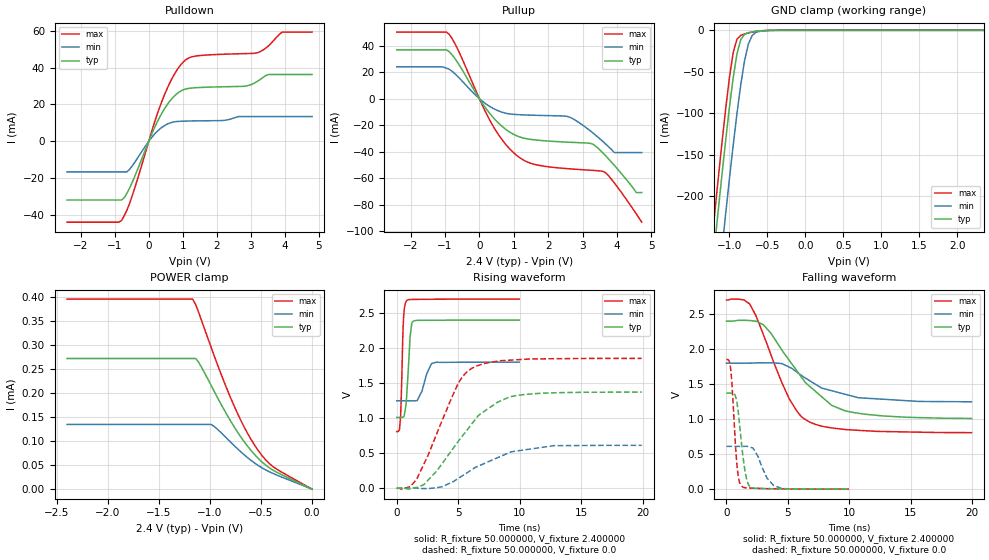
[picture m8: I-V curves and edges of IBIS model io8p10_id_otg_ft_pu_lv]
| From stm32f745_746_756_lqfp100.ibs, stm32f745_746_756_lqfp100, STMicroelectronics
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|   Model io8p10_id_otg_ft_pu_lv
[Model]  io8p10_id_otg_ft_pu_lv
Model_type I/O
Polarity   Non-Inverting
Enable   Active-Low
Vinl =   0.720000V
Vinh =   1.680000V
Vmeas =  1.200000V
Cref =   40.000000pF
Rref =   100.000000M
Vref =   0.0V
C_comp   2.229800pF   2.169700pF   2.325100pF
[Temperature Range]   25.000000   0.125000k   -40.000000
[Pullup Reference]   2.400000V   1.800000V   2.700000V
[Pulldown Reference]   0.0V   0.0V   0.0V
[POWER Clamp Reference]   2.400000V   1.800000V   2.700000V
[GND Clamp Reference]   0.0V   0.0V   0.0V
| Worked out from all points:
|   slope of the pulldown table from 0 to 0.36 V, typ, clamps not added: 25 ohm
|   slope of the pullup table from 0 to 0.36 V, typ, clamps not added: 27.7 ohm
|   GND clamp passes 1 mA (typ) near -0.62 V on its own axis
|   rising waveform, R_fixture 50.000000, V_fixture 2.400000: 20-80 % time 276ps typ, 615ps min, 181ps max; typ from 1.01 V to 2.4 V
|   rising waveform, R_fixture 50.000000, V_fixture 0.0: 20-80 % time 3.75ns typ, 4.05ns min, 2.68ns max; typ from 0.004 V to 1.37 V
|   falling waveform, R_fixture 50.000000, V_fixture 2.400000: 20-80 % time 3.95ns typ, 4ns min, 2.73ns max; typ from 2.4 V to 1.01 V
|   falling waveform, R_fixture 50.000000, V_fixture 0.0: 20-80 % time 532ps typ, 989ps min, 386ps max; typ from 1.37 V to 0.004 V
[Pulldown]
|Voltage   I(typ)   I(min)   I(max)
-2.4V     -31.73mA   -16.51mA   -43.74mA
-800mV    -31.73mA   -16.51mA   -42.87mA
-480mV    -21.97mA   -13.17mA   -29.21mA
80mV      3.63mA     1.966mA    5.014mA
480mV     18.15mA    8.737mA    26.02mA
800mV     25.37mA    10.72mA    37.77mA
1.12V     28.53mA    11.02mA    44.6mA
2.8V      29.84mA    13.46mA    47.53mA
3.2V      32.6mA     13.46mA    48.03mA
3.52V     36.23mA    13.46mA    51.75mA
3.92V     36.23mA    13.46mA    59.19mA
4.8V      36.23mA    13.46mA    59.19mA
[Pullup]
|Voltage   I(typ)   I(min)   I(max)
-2.4V     36.81mA    24.03mA    50.22mA
-960mV    36.81mA    22.97mA    50.22mA
-640mV    27.62mA    17.02mA    37.95mA
320mV     -11.75mA   -6.206mA   -17.08mA
960mV     -26.46mA   -11.81mA   -40.01mA
1.52V     -30.88mA   -12.51mA   -49.04mA
2.56V     -32.87mA   -13.48mA   -52.89mA
3.28V     -34.17mA   -25.52mA   -54.16mA
3.6V      -41.29mA   -32.61mA   -54.95mA
3.92V     -50.31mA   -40.7mA    -63.6mA
4.56V     -70.9mA    -40.7mA    -87.04mA
4.72V     -70.9mA    -40.7mA    -93.3mA
[GND_clamp]
|Voltage   I(typ)   I(min)   I(max)
-2.4V     -1.424A    -1.508A    -1.393A
-1.25V    -311.2mA   -401.9mA   -273.3mA
-1.2V     -265.4mA   -356.1mA   -227.2mA
-1.15V    -220.4mA   -310.8mA   -181.9mA
-1.1V     -176.3mA   -266.2mA   -137.9mA
-1.05V    -133.8mA   -222.5mA   -95.88mA
-950mV    -57.31mA   -138.9mA   -26.99mA
-900mV    -28.28mA   -100.4mA   -10.61mA
-850mV    -11.02mA   -65.55mA   -5.978mA
-750mV    -2.847mA   -16.51mA   -3.192mA
-600mV    -755.4uA   -1.17mA    -743.6uA
2.35V     0A         0A         0A
[POWER_clamp]
|Voltage   I(typ)   I(min)   I(max)
-2.4V     272.5uA    135uA      396.5uA
-1.17V    272.5uA    135uA      396.5uA
-1.14V    272.5uA    135uA      384.7uA
-1.11V    264.2uA    135uA      368uA
-990mV    216.8uA    135uA      296.5uA
-870mV    168.8uA    113.3uA    228.2uA
-750mV    125.6uA    88.19uA    167.1uA
-660mV    97.6uA     70.82uA    127.5uA
-570mV    73.91uA    55.62uA    94.12uA
-480mV    54.73uA    43.14uA    67.37uA
-390mV    40.65uA    33.48uA    48.23uA
0V        0A         0A         0A
[Ramp]
| variable   typ   min   max
dV/dt_r  0.82171/3.74541n   0.36677/4.05475n   1.11308/2.68853n
dV/dt_f  0.83058/3.95989n   0.33120/4.06752n   1.13384/2.73321n
R_load = 50.000000
[Rising Waveform]
R_fixture= 50.000000
V_fixture= 2.400000
V_fixture_min= 1.800000
V_fixture_max= 2.700000
|time   V(typ)   V(min)   V(max)
0s        1.011V     1.249V     809.2mV
220.2ps   1.011V     1.249V     836.1mV
300.3ps   1.011V     1.249V     995.6mV
560.6ps   1.02V      1.249V     2.447V
800.8ps   1.296V     1.249V     2.674V
1.081ns   2.143V     1.249V     2.693V
1.341ns   2.383V     1.247V     2.694V
2.042ns   2.396V     1.382V     2.695V
2.843ns   2.397V     1.78V      2.697V
9.97ns    2.4V       1.8V       2.699V
[Rising Waveform]
R_fixture= 50.000000
V_fixture= 0.0
V_fixture_min= 0.0
V_fixture_max= 0.0
|time   V(typ)   V(min)   V(max)
0s        3.745mV    3.286mV    4.353mV
1.121ns   -5.002mV   3.344mV    27.75mV
1.642ns   12.38mV    2.72mV     138mV
3.283ns   253.4mV    9.922mV    791.1mV
4.965ns   661.2mV    137.1mV    1.484V
6.206ns   940.8mV    277.4mV    1.721V
8.168ns   1.225V     434.7mV    1.813V
9.409ns   1.313V     523.7mV    1.83V
12.77ns   1.362V     608.8mV    1.849V
19.94ns   1.373V     613.5mV    1.853V
[Falling Waveform]
R_fixture= 50.000000
V_fixture= 2.400000
V_fixture_min= 1.800000
V_fixture_max= 2.700000
|time   V(typ)   V(min)   V(max)
0s        2.4V       1.8V       2.699V
1.121ns   2.41V      1.8V       2.71V
1.882ns   2.407V     1.801V     2.645V
3.003ns   2.348V     1.805V     2.207V
5.125ns   1.836V     1.742V     1.287V
6.046ns   1.614V     1.632V     1.047V
6.807ns   1.464V     1.546V     957.1mV
8.569ns   1.198V     1.406V     876.4mV
9.89ns    1.111V     1.346V     850.7mV
19.94ns   1.011V     1.249V     809.2mV
[Falling Waveform]
R_fixture= 50.000000
V_fixture= 0.0
V_fixture_min= 0.0
V_fixture_max= 0.0
|time   V(typ)   V(min)   V(max)
0s        1.373V     613.5mV    1.853V
340.3ps   1.373V     613.5mV    1.723V
440.4ps   1.373V     613.5mV    1.525V
700.7ps   1.349V     613.4mV    737.2mV
940.9ps   1.131V     613.2mV    211.5mV
1.241ns   630.2mV    613mV      45.65mV
1.682ns   115.7mV    614.8mV    20.53mV
2.042ns   28.2mV     595.9mV    17.62mV
3.844ns   9.408mV    55.16mV    8.721mV
9.97ns    3.745mV    3.286mV    4.353mV
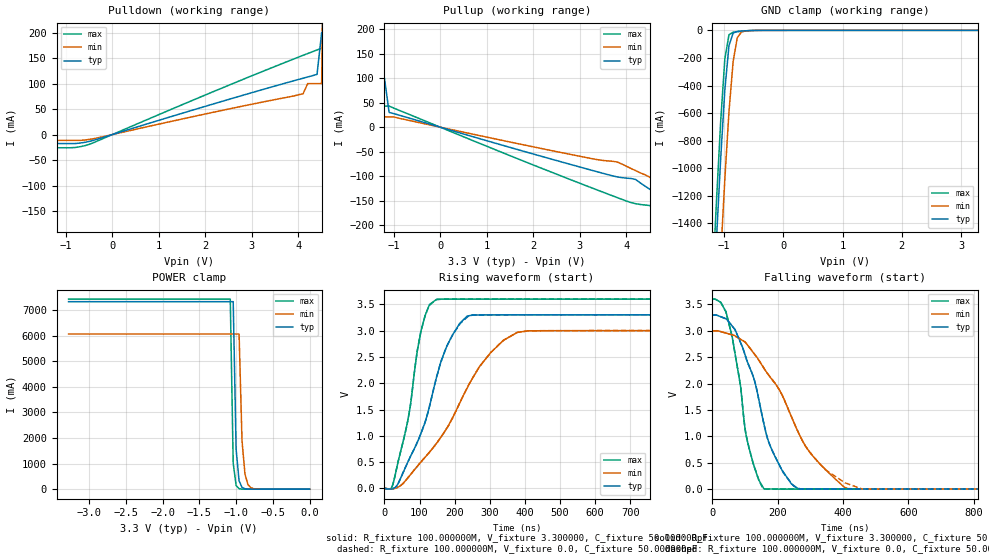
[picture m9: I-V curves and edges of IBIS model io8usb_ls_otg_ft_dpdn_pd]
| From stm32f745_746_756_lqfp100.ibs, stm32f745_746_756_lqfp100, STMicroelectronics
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|   Model io8usb_ls_otg_ft_dpdn_pd
[Model]  io8usb_ls_otg_ft_dpdn_pd
Model_type I/O
Polarity   Non-Inverting
Enable   Active-Low
Vinl =   0.990000V
Vinh =   2.310000V
Vmeas =  1.650000V
Cref =   50.000000pF
Rref =   100.000000M
Vref =   0.0V
C_comp   8.255900pF   7.991100pF   8.650600pF
[Temperature Range]   25.000000   0.125000k   -40.000000
[Pullup Reference]   3.300000V   3.000000V   3.600000V
[Pulldown Reference]   0.0V   0.0V   0.0V
[POWER Clamp Reference]   3.300000V   3.000000V   3.600000V
[GND Clamp Reference]   0.0V   0.0V   0.0V
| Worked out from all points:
|   slope of the pulldown table from 0 to 0.495 V, typ, clamps not added: 35.6 ohm
|   slope of the pullup table from 0 to 0.495 V, typ, clamps not added: 36.1 ohm
|   GND clamp passes 1 mA (typ) near -0.52 V on its own axis
|   POWER clamp passes 1 mA (typ) near -0.81 V on its own axis
|   rising waveform, R_fixture 100.000000M, V_fixture 3.300000, C_fixture 50.000000pF: 20-80 % time 95.9ns typ, 164ns min, 54.2ns max; typ from 0 V to 3.3 V
|   rising waveform, R_fixture 100.000000M, V_fixture 0.0, C_fixture 50.000000pF: 20-80 % time 95.9ns typ, 164ns min, 54ns max; typ from 0 V to 3.3 V
|   falling waveform, R_fixture 100.000000M, V_fixture 3.300000, C_fixture 50.000000pF: 20-80 % time 93.4ns typ, 165ns min, 53.9ns max; typ from 3.3 V to 0 V
|   falling waveform, R_fixture 100.000000M, V_fixture 0.0, C_fixture 50.000000pF: 20-80 % time 93.5ns typ, 165ns min, 53.9ns max; typ from 3.3 V to 0 V
[Pulldown]
|Voltage   I(typ)   I(min)   I(max)
-3.3V     -182mA     -11.47mA   -25.86mA
-3.2V     -17.62mA   -11.47mA   -25.86mA
-600mV    -15.36mA   -10.76mA   -22.01mA
4.1V      110.5mA    80mA       155.3mA
4.2V      112.9mA    100mA      158.9mA
4.4V      118mA      100mA      165.9mA
4.5V      200mA      100mA      169.3mA
4.6V      200mA      1A         172.7mA
4.7V      200mA      1A         176mA
4.8V      1A         1A         200mA
5.4V      1A         1A         1A
6.6V      1A         1A         1A
[Pullup]
|Voltage   I(typ)   I(min)   I(max)
-3.3V     1A         1A         1A
-1.9V     1A         1A         1A
-1.8V     100mA      1A         1A
-1.7V     100mA      1A         100mA
-1.6V     100mA      1A         100mA
-1.5V     100mA      21mA       100mA
-1.3V     100mA      21mA       100mA
-1.2V     100mA      21mA       43mA
-1.1V     30mA       21mA       43mA
4.2V      -106.8mA   -88.8mA    -156.2mA
5V        -156.6mA   -125mA     -203.2mA
6.6V      -223mA     -161mA     -321mA
[GND_clamp]
|Voltage   I(typ)   I(min)   I(max)
-3.3V     -9.433A    -9.435A    -9.911A
-1.2V     -2.116A    -2.846A    -1.847A
-1.13V    -1.505A    -2.23A     -1.23A
-1.06V    -930.4mA   -1.637A    -658.9mA
-990mV    -432.7mA   -1.08A     -207.3mA
-920mV    -110.5mA   -590.3mA   -31.59mA
-850mV    -19.84mA   -226.8mA   -13.66mA
-780mV    -8.32mA    -54.05mA   -9.517mA
-710mV    -5.29mA    -11.97mA   -6.272mA
-640mV    -3.236mA   -4.296mA   -3.585mA
3.28V     149.6uA    102.1uA    206.8uA
[POWER_clamp]
|Voltage   I(typ)   I(min)   I(max)
-3.28V    7.328A     6.064A     7.43A
-1.08V    7.328A     6.064A     7.43A
-1.04V    7.328A     6.064A     1.015A
-1V       1.545A     6.064A     138.6mA
-960mV    325.6mA    6.064A     18.93mA
-920mV    68.64mA    1.89A      2.585mA
-880mV    14.47mA    589mA      353uA
-840mV    3.05mA     183.6mA    105.9uA
-800mV    642.9uA    57.21mA    105.9uA
-720mV    28.59uA    5.557mA    105.9uA
0V        0A         0A         0A
[Ramp]
| variable   typ   min   max
dV/dt_r  1.45411/0.11060u   1.20609/0.19723u   1.71850/64.27239n
dV/dt_f  1.45867/95.20862n   1.20947/0.16655u   1.72113/55.15060n
R_load = 100.000000
[Rising Waveform]
R_fixture= 100.000000M
V_fixture= 3.300000
V_fixture_min= 3.000000
V_fixture_max= 3.600000
C_fixture= 50.000000pF
|time   V(typ)   V(min)   V(max)
0s        106.1uV    63.26uV    178.2uV
25.36ns   -335.1uV   -4.107mV   112.1mV
69.4ns    541.4mV    225mV      1.399V
104.1ns   1.051V     505.2mV    2.993V
148.1ns   2.11V      856.6mV    3.591V
177.5ns   2.703V     1.145V     3.598V
234.9ns   3.271V     1.901V     3.599V
303ns     3.298V     2.584V     3.599V
379ns     3.299V     2.966V     3.599V
1.333us   3.299V     2.999V     3.599V
[Rising Waveform]
R_fixture= 100.000000M
V_fixture= 0.0
V_fixture_min= 0.0
V_fixture_max= 0.0
C_fixture= 50.000000pF
|time   V(typ)   V(min)   V(max)
0s        104.9uV    61.81uV    177.3uV
25.36ns   -346uV     -4.117mV   112.1mV
69.4ns    541.4mV    225mV      1.399V
102.8ns   1.028V     495mV      2.954V
126.8ns   1.521V     679.2mV    3.472V
146.8ns   2.072V     845mV      3.586V
193.5ns   2.912V     1.336V     3.598V
240.2ns   3.282V     1.971V     3.599V
379ns     3.299V     2.966V     3.599V
1.333us   3.299V     2.999V     3.599V
[Falling Waveform]
R_fixture= 100.000000M
V_fixture= 3.300000
V_fixture_min= 3.000000
V_fixture_max= 3.600000
C_fixture= 50.000000pF
|time   V(typ)   V(min)   V(max)
0s        3.299V     2.999V     3.599V
41.37ns   3.229V     2.958V     3.363V
82.75ns   2.827V     2.854V     2.081V
104.1ns   2.463V     2.758V     991.6mV
130.8ns   2.012V     2.542V     373.8mV
157.5ns   1.239V     2.294V     5.569mV
241.6ns   99.22mV    1.374V     199.9uV
304.3ns   206.7uV    649.3mV    191.8uV
415.1ns   107.6uV    9.906mV    173.9uV
1.333us   106.2uV    63.55uV    182.1uV
[Falling Waveform]
R_fixture= 100.000000M
V_fixture= 0.0
V_fixture_min= 0.0
V_fixture_max= 0.0
C_fixture= 50.000000pF
|time   V(typ)   V(min)   V(max)
0s        3.299V     2.999V     3.599V
41.37ns   3.229V     2.958V     3.363V
81.41ns   2.846V     2.859V     2.131V
105.4ns   2.438V     2.747V     953.8mV
156.2ns   1.276V     2.307V     4.082mV
193.5ns   593.2mV    1.991V     272.8uV
249.6ns   52.64mV    1.258V     182.8uV
344.3ns   126.3uV    373.6mV    177.8uV
457.8ns   105.3uV    980.6uV    177.4uV
1.333us   105.1uV    59.65uV    177.4uV
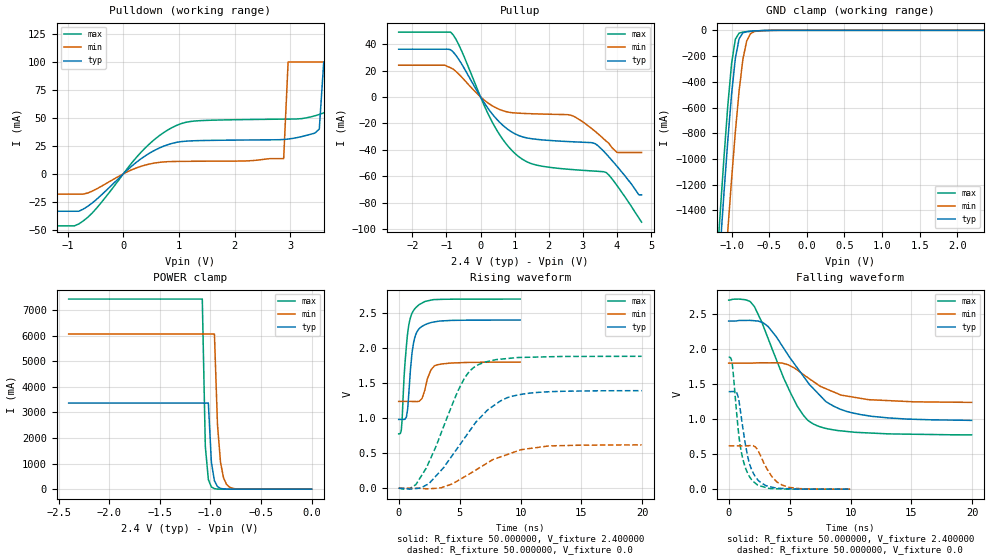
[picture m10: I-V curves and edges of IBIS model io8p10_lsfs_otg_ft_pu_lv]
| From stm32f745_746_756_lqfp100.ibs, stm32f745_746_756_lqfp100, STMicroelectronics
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|   Model io8p10_lsfs_otg_ft_pu_lv
[Model]  io8p10_lsfs_otg_ft_pu_lv
Model_type I/O
Polarity   Non-Inverting
Enable   Active-Low
Vinl =   0.720000V
Vinh =   1.680000V
Vmeas =  1.200000V
Cref =   40.000000pF
Rref =   100.000000M
Vref =   0.0V
C_comp   7.971100pF   7.737700pF   8.264100pF
[Temperature Range]   25.000000   0.125000k   -40.000000
[Pullup Reference]   2.400000V   1.800000V   2.700000V
[Pulldown Reference]   0.0V   0.0V   0.0V
[POWER Clamp Reference]   2.400000V   1.800000V   2.700000V
[GND Clamp Reference]   0.0V   0.0V   0.0V
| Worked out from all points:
|   slope of the pulldown table from 0 to 0.36 V, typ, clamps not added: 24.1 ohm
|   slope of the pullup table from 0 to 0.36 V, typ, clamps not added: 26.8 ohm
|   GND clamp passes 1 mA (typ) near -0.52 V on its own axis
|   POWER clamp passes 1 mA (typ) near -0.81 V on its own axis
|   rising waveform, R_fixture 50.000000, V_fixture 2.400000: 20-80 % time 479ps typ, 594ps min, 489ps max; typ from 0.983 V to 2.4 V
|   rising waveform, R_fixture 50.000000, V_fixture 0.0: 20-80 % time 3.67ns typ, 4.12ns min, 2.71ns max; typ from 0.001 V to 1.39 V
|   falling waveform, R_fixture 50.000000, V_fixture 2.400000: 20-80 % time 3.76ns typ, 3.38ns min, 2.85ns max; typ from 2.4 V to 0.983 V
|   falling waveform, R_fixture 50.000000, V_fixture 0.0: 20-80 % time 918ps typ, 1.28ns min, 800ps max; typ from 1.39 V to 0.001 V
[Pulldown]
|Voltage   I(typ)   I(min)   I(max)
-2.4V     -33.44mA   -18.11mA   -46.51mA
-800mV    -33.44mA   -18.11mA   -44.78mA
1.04V     28.81mA    11.14mA    44.91mA
2.88V     30.7mA     13.62mA    48.89mA
2.96V     31.1mA     100mA      48.94mA
3.52V     40mA       100mA      53.06mA
3.6V      100mA      100mA      54.54mA
3.92V     100mA      100mA      60mA
4V        100mA      100mA      100mA
4.4V      100mA      100mA      100mA
4.48V     100mA      100mA      1A
4.8V      100mA      100mA      1A
[Pullup]
|Voltage   I(typ)   I(min)   I(max)
-2.4V     36.11mA    24mA       49.05mA
-880mV    35.74mA    22.13mA    49.05mA
-640mV    28.44mA    17.3mA     39.59mA
320mV     -12.14mA   -6.322mA   -17.91mA
960mV     -27.18mA   -12mA      -41.54mA
1.52V     -31.65mA   -12.71mA   -50.67mA
2.64V     -33.82mA   -13.73mA   -54.81mA
3.28V     -34.63mA   -24.4mA    -55.96mA
3.68V     -43mA      -33.4mA    -57.12mA
4V        -52.4mA    -42mA      -67mA
4.64V     -74mA      -42mA      -91.5mA
4.72V     -74mA      -42mA      -94.7mA
[GND_clamp]
|Voltage   I(typ)   I(min)   I(max)
-2.4V     -9.766A    -9.942A    -9.572A
-1.2V     -2.124A    -2.851A    -1.855A
-1.15V    -1.682A    -2.408A    -1.408A
-1.1V     -1.256A    -1.975A    -979.8mA
-1.05V    -854.9mA   -1.556A    -584.5mA
-1V       -496.5mA   -1.158A    -257.5mA
-950mV    -217.7mA   -789.6mA   -69.52mA
-900mV    -65.57mA   -469.8mA   -21.5mA
-850mV    -19.64mA   -226.4mA   -13.56mA
-800mV    -9.753mA   -84.21mA   -10.47mA
-700mV    -4.923mA   -9.884mA   -5.807mA
2.35V     0A         0A         0A
[POWER_clamp]
|Voltage   I(typ)   I(min)   I(max)
-2.4V     3.365A     6.064A     7.43A
-1.08V    3.365A     6.064A     7.43A
-1.05V    3.365A     6.064A     1.669A
-1.02V    3.365A     6.064A     375.2mA
-990mV    1.047A     6.064A     84.45mA
-960mV    325.8mA    6.064A     19.12mA
-930mV    101.4mA    2.529A     4.431mA
-900mV    31.63mA    1.055A     1.12mA
-870mV    9.908mA    440.1mA    365.5uA
-840mV    3.145mA    183.6mA    185.6uA
-720mV    90.15uA    5.596mA    88.88uA
0V        0A         0A         0A
[Ramp]
| variable   typ   min   max
dV/dt_r  0.83517/3.67211n   0.37088/4.11830n   1.12915/2.71168n
dV/dt_f  0.84704/3.76297n   0.33606/3.40725n   1.15349/2.85178n
R_load = 50.000000
[Rising Waveform]
R_fixture= 50.000000
V_fixture= 2.400000
V_fixture_min= 1.800000
V_fixture_max= 2.700000
|time   V(typ)   V(min)   V(max)
0s        982.7mV    1.24V      776.2mV
220.2ps   982.4mV    1.24V      838.2mV
440.4ps   983.7mV    1.24V      1.577V
640.6ps   1.023V     1.24V      2.043V
820.8ps   1.325V     1.24V      2.318V
1.101ns   1.939V     1.239V     2.499V
1.421ns   2.201V     1.238V     2.58V
1.922ns   2.311V     1.283V     2.643V
2.963ns   2.375V     1.75V      2.692V
9.97ns    2.4V       1.8V       2.7V
[Rising Waveform]
R_fixture= 50.000000
V_fixture= 0.0
V_fixture_min= 0.0
V_fixture_max= 0.0
|time   V(typ)   V(min)   V(max)
0s        869.1uV    836uV      780uV
1.441ns   -2.742mV   898.5uV    60.47mV
2.482ns   66.82mV    -6.054mV   373.2mV
3.483ns   256mV      8.272mV    787.9mV
5.125ns   647.1mV    136.2mV    1.481V
5.726ns   794.6mV    197.4mV    1.649V
6.406ns   957.4mV    269.1mV    1.751V
8.368ns   1.248V     448.8mV    1.842V
10.21ns   1.345V     555mV      1.868V
19.94ns   1.393V     619.1mV    1.883V
[Falling Waveform]
R_fixture= 50.000000
V_fixture= 2.400000
V_fixture_min= 1.800000
V_fixture_max= 2.700000
|time   V(typ)   V(min)   V(max)
0s        2.4V       1.8V       2.7V
1.441ns   2.41V      1.8V       2.702V
2.122ns   2.405V     1.801V     2.604V
3.243ns   2.32V      1.804V     2.149V
5.125ns   1.853V     1.754V     1.358V
6.126ns   1.614V     1.638V     1.058V
6.967ns   1.434V     1.535V     930.1mV
8.609ns   1.186V     1.389V     847.1mV
10.85ns   1.065V     1.296V     808.5mV
19.94ns   982.7mV    1.24V      776.2mV
[Falling Waveform]
R_fixture= 50.000000
V_fixture= 0.0
V_fixture_min= 0.0
V_fixture_max= 0.0
|time   V(typ)   V(min)   V(max)
0s        1.393V     619.1mV    1.883V
300.3ps   1.394V     619.1mV    1.779V
760.8ps   1.33V      619mV      890.5mV
1.041ns   1.024V     618.7mV    529.6mV
1.562ns   465.4mV    620.4mV    226.8mV
1.922ns   265.2mV    622.2mV    125.9mV
2.683ns   88.79mV    451.8mV    42.49mV
3.604ns   27.58mV    167.1mV    9.267mV
4.404ns   10.98mV    57.93mV    4.499mV
9.97ns    869.1uV    836uV      780uV
